VERSION 5.7 ;
  NOWIREEXTENSIONATPIN ON ;
  DIVIDERCHAR "/" ;
  BUSBITCHARS "[]" ;
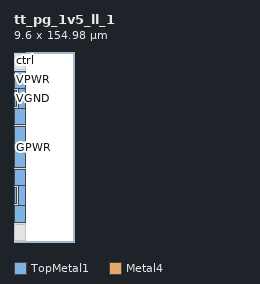
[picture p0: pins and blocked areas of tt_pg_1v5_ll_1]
MACRO tt_pg_1v5_ll_1
  CLASS BLOCK ;
  FOREIGN tt_pg_1v5_ll_1 ;
  ORIGIN 0.000 0.000 ;
  SIZE 9.600 BY 154.980 ;
  PIN VGND
    DIRECTION INPUT ;
    USE GROUND ;
    PORT
      LAYER TopMetal1 ;
        RECT 0.000 31.120 2.100 44.480 ;
    END
    PORT
      LAYER TopMetal1 ;
        RECT 0.000 110.500 2.100 123.860 ;
    END
  END VGND
  PIN VPWR
    DIRECTION INPUT ;
    USE POWER ;
    PORT
      LAYER TopMetal1 ;
        RECT 0.000 16.120 9.600 29.480 ;
    END
    PORT
      LAYER TopMetal1 ;
        RECT 0.000 46.120 9.600 59.480 ;
    END
    PORT
      LAYER TopMetal1 ;
        RECT 3.740 29.480 9.600 46.120 ;
    END
    PORT
      LAYER TopMetal1 ;
        RECT 0.000 95.500 9.600 108.860 ;
    END
    PORT
      LAYER TopMetal1 ;
        RECT 0.000 125.500 9.600 138.860 ;
    END
    PORT
      LAYER TopMetal1 ;
        RECT 3.740 108.860 9.600 125.500 ;
    END
  END VPWR
  PIN GPWR
    DIRECTION OUTPUT ;
    USE POWER ;
    PORT
      LAYER TopMetal1 ;
        RECT 0.000 61.120 9.600 93.860 ;
    END
  END GPWR
  PIN ctrl
    DIRECTION INPUT ;
    USE SIGNAL ;
    ANTENNAGATEAREA 0.915200 ;
    PORT
      LAYER Metal4 ;
        RECT 0.000 154.480 9.600 154.980 ;
    END
  END ctrl
  OBS
      LAYER GatPoly ;
        RECT 0.340 0.540 9.260 154.490 ;
      LAYER Metal1 ;
        RECT 0.000 0.610 9.600 154.420 ;
      LAYER Metal2 ;
        RECT 0.000 0.300 9.600 154.980 ;
      LAYER Metal3 ;
        RECT 0.000 1.000 9.600 154.980 ;
      LAYER Metal4 ;
        RECT 0.000 1.000 9.600 153.980 ;
      LAYER Metal5 ;
        RECT 0.000 1.000 9.600 153.980 ;
      LAYER TopMetal1 ;
        RECT 0.000 140.500 9.600 153.980 ;
        RECT 0.000 1.000 9.600 14.480 ;
  END
END tt_pg_1v5_ll_1
END LIBRARY

